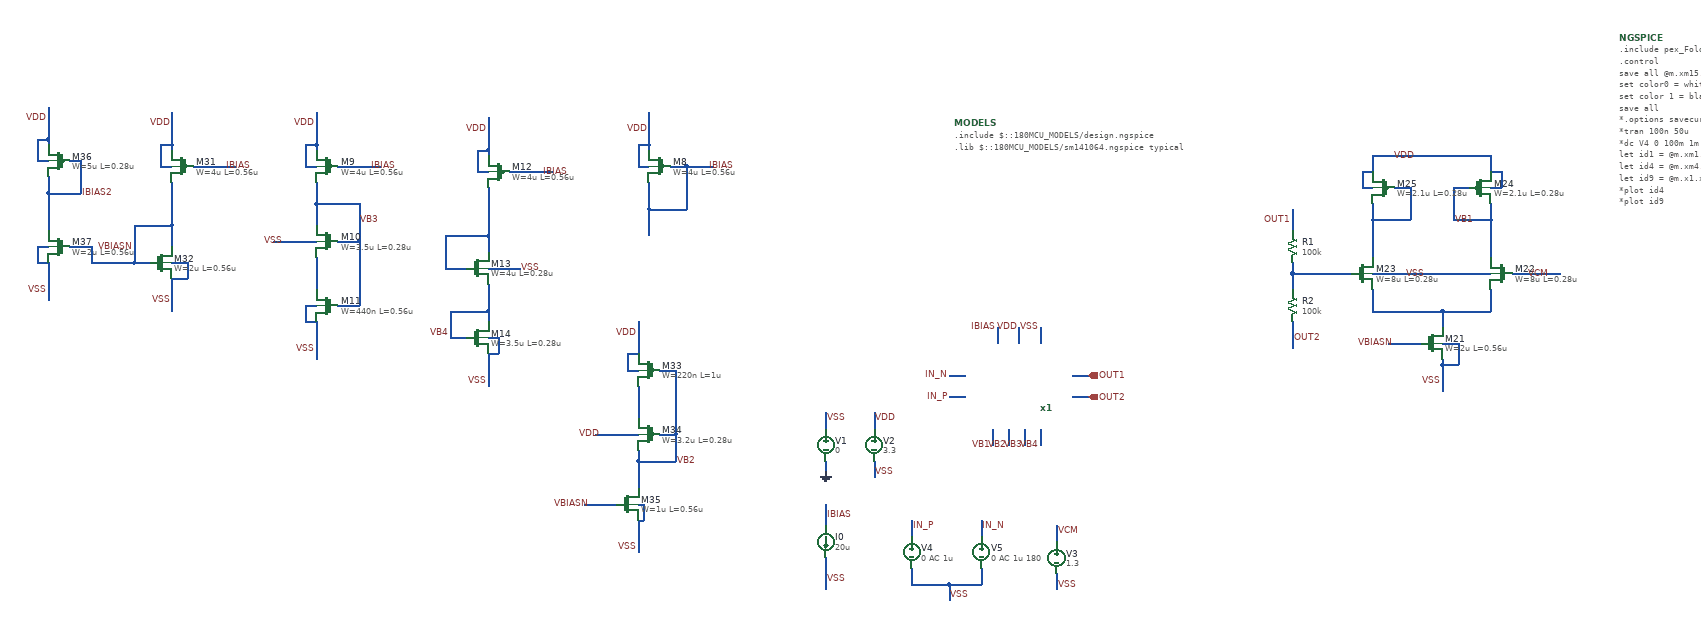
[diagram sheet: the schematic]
v {xschem version=3.1.0 file_version=1.2
}
G {}
K {}
V {}
S {}
E {}
N 10 -20 40 -20 {
lab=IN_N}
N 10 20 40 20 {
lab=IN_P}
N 240 -20 270 -20 {
lab=OUT1}
N 240 20 270 20 {
lab=OUT2}
N 90 80 90 110 {
lab=VB1}
N 120 80 120 110 {
lab=VB2}
N 150 80 150 110 {
lab=VB3}
N 180 80 180 110 {
lab=VB4}
N 100 -110 100 -80 {
lab=IBIAS}
N 140 -110 140 -80 {
lab=VDD}
N 180 -110 180 -80 {
lab=VSS}
N -220 140 -220 160 {
lab=GND}
N -220 50 -220 80 {
lab=VSS}
N -130 50 -130 80 {
lab=VDD}
N -130 140 -130 170 {
lab=VSS}
N 210 260 210 290 {
lab=VCM}
N 210 350 210 380 {
lab=VSS}
N -220 220 -220 260 {
lab=IBIAS}
N -220 320 -220 380 {
lab=VSS}
N -60 250 -60 280 {
lab=IN_P}
N -60 340 -60 370 {
lab=VSS}
N 70 250 70 280 {
lab=IN_N}
N 70 340 70 370 {
lab=VSS}
N 10 370 70 370 {
lab=VSS}
N 10 370 10 400 {
lab=VSS}
N -60 370 10 370 {
lab=VSS}
N -850 -440 -850 -430 {
lab=VDD}
N -870 -400 -850 -400 {
lab=VDD}
N -870 -440 -870 -400 {
lab=VDD}
N -870 -440 -850 -440 {
lab=VDD}
N -810 -400 -730 -400 {
lab=IBIAS}
N -850 -370 -850 -280 {
lab=#net1}
N -850 -280 -850 -250 {
lab=#net1}
N -850 -220 -790 -220 {
lab=VSS}
N -930 -220 -890 -220 {
lab=#net1}
N -930 -280 -930 -220 {
lab=#net1}
N -930 -280 -850 -280 {
lab=#net1}
N -850 -140 -850 -120 {
lab=VB4}
N -920 -90 -890 -90 {
lab=VB4}
N -920 -140 -920 -90 {
lab=VB4}
N -920 -140 -850 -140 {
lab=VB4}
N -850 -60 -850 0 {
lab=VSS}
N -850 -90 -830 -90 {
lab=VSS}
N -830 -90 -830 -60 {
lab=VSS}
N -850 -60 -830 -60 {
lab=VSS}
N -550 -450 -550 -440 {
lab=VDD}
N -570 -410 -550 -410 {
lab=VDD}
N -570 -450 -570 -410 {
lab=VDD}
N -570 -450 -550 -450 {
lab=VDD}
N -480 -410 -430 -410 {
lab=IBIAS}
N -550 -380 -550 -330 {
lab=IBIAS}
N -550 -330 -480 -330 {
lab=IBIAS}
N -480 -410 -480 -330 {
lab=IBIAS}
N -550 -330 -550 -280 {
lab=IBIAS}
N -1170 -450 -1170 -440 {
lab=VDD}
N -1190 -410 -1170 -410 {
lab=VDD}
N -1190 -450 -1190 -410 {
lab=VDD}
N -1190 -450 -1170 -450 {
lab=VDD}
N -1130 -410 -1050 -410 {
lab=IBIAS}
N -1170 -120 -1170 -50 {
lab=VSS}
N -1130 -150 -1090 -150 {
lab=VB3}
N -1170 -240 -1170 -180 {
lab=#net2}
N -1130 -270 -1090 -270 {
lab=VB3}
N -1090 -270 -1090 -150 {
lab=VB3}
N -1090 -340 -1090 -270 {
lab=VB3}
N -1170 -340 -1090 -340 {
lab=VB3}
N -1170 -380 -1170 -340 {
lab=VB3}
N -1170 -340 -1170 -300 {
lab=VB3}
N -1250 -270 -1170 -270 {
lab=VSS}
N -1190 -150 -1170 -150 {
lab=VSS}
N -1190 -150 -1190 -120 {
lab=VSS}
N -1190 -120 -1170 -120 {
lab=VSS}
N -1440 -450 -1440 -440 {
lab=VDD}
N -1460 -410 -1440 -410 {
lab=VDD}
N -1460 -450 -1460 -410 {
lab=VDD}
N -1460 -450 -1440 -450 {
lab=VDD}
N -1400 -410 -1320 -410 {
lab=IBIAS}
N -1440 -300 -1440 -260 {
lab=VBIASN}
N -1440 -200 -1440 -140 {
lab=VSS}
N -1440 -230 -1410 -230 {
lab=VSS}
N -1410 -230 -1410 -200 {
lab=VSS}
N -1440 -200 -1410 -200 {
lab=VSS}
N -1510 -230 -1480 -230 {
lab=VBIASN}
N -1510 -300 -1510 -230 {
lab=VBIASN}
N -1510 -300 -1440 -300 {
lab=VBIASN}
N -570 140 -570 190 {
lab=VB2}
N -570 220 -560 220 {
lab=VSS}
N -560 220 -560 250 {
lab=VSS}
N -570 250 -560 250 {
lab=VSS}
N -570 250 -570 310 {
lab=VSS}
N -670 220 -610 220 {
lab=VBIASN}
N -570 0 -570 60 {
lab=#net3}
N -650 90 -570 90 {
lab=VDD}
N -570 -120 -570 -60 {
lab=VDD}
N -530 -30 -500 -30 {
lab=VB2}
N -500 90 -500 140 {
lab=VB2}
N -570 140 -500 140 {
lab=VB2}
N -530 90 -500 90 {
lab=VB2}
N -590 -30 -570 -30 {
lab=VDD}
N -590 -60 -590 -30 {
lab=VDD}
N -590 -60 -570 -60 {
lab=VDD}
N -1670 -460 -1670 -450 {
lab=VDD}
N -1690 -420 -1670 -420 {
lab=VDD}
N -1690 -460 -1690 -420 {
lab=VDD}
N -1690 -460 -1670 -460 {
lab=VDD}
N -1670 -230 -1670 -160 {
lab=VSS}
N -1690 -260 -1670 -260 {
lab=VSS}
N -1690 -260 -1690 -230 {
lab=VSS}
N -1690 -230 -1670 -230 {
lab=VSS}
N -1630 -260 -1590 -260 {
lab=VBIASN}
N -1590 -260 -1590 -230 {
lab=VBIASN}
N -1590 -230 -1510 -230 {
lab=VBIASN}
N -1670 -360 -1670 -290 {
lab=IBIAS2}
N -1630 -420 -1610 -420 {
lab=IBIAS2}
N -1610 -420 -1610 -360 {
lab=IBIAS2}
N -1670 -360 -1610 -360 {
lab=IBIAS2}
N -850 -500 -850 -440 {
lab=VDD}
N -850 -190 -850 -140 {
lab=VB4}
N -550 -510 -550 -450 {
lab=VDD}
N -510 -410 -480 -410 {
lab=IBIAS}
N -1170 -510 -1170 -450 {
lab=VDD}
N -1440 -510 -1440 -450 {
lab=VDD}
N -1440 -380 -1440 -300 {
lab=VBIASN}
N -570 120 -570 140 {
lab=VB2}
N -500 -30 -500 90 {
lab=VB2}
N -1670 -520 -1670 -460 {
lab=VDD}
N -1670 -390 -1670 -360 {
lab=IBIAS2}
N 800 -430 800 -400 {
lab=VDD}
N 800 -430 1020 -430 {
lab=VDD}
N 1020 -430 1020 -400 {
lab=VDD}
N 1020 -310 1020 -240 {
lab=VB1}
N 800 -310 800 -240 {
lab=#net4}
N 840 -370 870 -370 {
lab=#net4}
N 870 -370 870 -310 {
lab=#net4}
N 800 -310 870 -310 {
lab=#net4}
N 950 -370 980 -370 {
lab=VB1}
N 950 -370 950 -310 {
lab=VB1}
N 950 -310 1020 -310 {
lab=VB1}
N 1020 -180 1020 -140 {
lab=#net5}
N 930 -140 1020 -140 {
lab=#net5}
N 800 -180 800 -140 {
lab=#net5}
N 930 -140 930 -110 {
lab=#net5}
N 930 -40 930 10 {
lab=VSS}
N 830 -80 890 -80 {
lab=VBIASN}
N 650 -330 650 -290 {
lab=OUT1}
N 650 -210 650 -180 {
lab=#net6}
N 650 -120 650 -70 {
lab=OUT2}
N 650 -210 760 -210 {
lab=#net6}
N 1060 -210 1150 -210 {
lab=VCM}
N 780 -370 800 -370 {
lab=VDD}
N 780 -400 780 -370 {
lab=VDD}
N 780 -400 800 -400 {
lab=VDD}
N 1020 -370 1040 -370 {
lab=VDD}
N 1040 -400 1040 -370 {
lab=VDD}
N 1020 -400 1040 -400 {
lab=VDD}
N 800 -210 1020 -210 {
lab=VSS}
N 930 -80 960 -80 {
lab=VSS}
N 960 -80 960 -40 {
lab=VSS}
N 930 -40 960 -40 {
lab=VSS}
N 800 -340 800 -310 {
lab=#net4}
N 1020 -340 1020 -310 {
lab=VB1}
N 800 -140 930 -140 {
lab=#net5}
N 650 -230 650 -210 {
lab=#net6}
N 930 -50 930 -40 {
lab=VSS}
C {devices/lab_pin.sym} 10 -20 0 0 {name=p1 sig_type=std_logic lab=IN_N}
C {devices/lab_pin.sym} 10 20 0 0 {name=p2 sig_type=std_logic lab=IN_P}
C {devices/lab_pin.sym} 100 -110 1 0 {name=p3 sig_type=std_logic lab=IBIAS}
C {devices/lab_pin.sym} 140 -110 1 0 {name=p4 sig_type=std_logic lab=VDD}
C {devices/lab_pin.sym} 180 -110 1 0 {name=p5 sig_type=std_logic lab=VSS}
C {devices/lab_pin.sym} 90 110 3 0 {name=p6 sig_type=std_logic lab=VB1}
C {devices/lab_pin.sym} 120 110 3 0 {name=p7 sig_type=std_logic lab=VB2}
C {devices/lab_pin.sym} 150 110 3 0 {name=p8 sig_type=std_logic lab=VB3}
C {devices/lab_pin.sym} 180 110 3 0 {name=p9 sig_type=std_logic lab=VB4}
C {devices/opin.sym} 270 -20 0 0 {name=p10 lab=OUT1}
C {devices/opin.sym} 270 20 0 0 {name=p11 lab=OUT2}
C {devices/code_shown.sym} 20 -490 0 0 {name=MODELS only_toplevel=true
format="tcleval( @value )"
value="
.include $::180MCU_MODELS/design.ngspice
.lib $::180MCU_MODELS/sm141064.ngspice typical
"}
C {devices/vsource.sym} -220 110 0 0 {name=V1 value=0}
C {devices/gnd.sym} -220 160 0 0 {name=l1 lab=GND}
C {devices/lab_pin.sym} -220 60 0 1 {name=p33 sig_type=std_logic lab=VSS}
C {devices/vsource.sym} -130 110 0 0 {name=V2 value=3.3}
C {devices/lab_pin.sym} -130 60 0 1 {name=p34 sig_type=std_logic lab=VDD}
C {devices/lab_pin.sym} -130 160 0 1 {name=p35 sig_type=std_logic lab=VSS}
C {devices/code_shown.sym} 1260 -650 0 0 {name=NGSPICE only_toplevel=true
value="
.include "pex_Folded_Diff_Op_Amp_Layout.spice"
.control
save all @m.xm15.m0[id] @m.xm1.m0[id] @m.xm4.m0[id] @m.x1.xm9.m0[id]
set color0 = white
set color 1 = black
save all
*.options savecurrents

*tran 100n 50u
*dc V4 0 100m 1m
let id1 = @m.xm1.m0[id] 
let id4 = @m.xm4.m0[id]
let id9 = @m.x1.xm9.m0[id]
*plot id4 
*plot id9
plot v(OUT1) v(OUT2)
*plot v(IN1) v(IN2)
*plot v(IN1P) v(IN1N)
*print mean(@m.xm2.m0[vds]) mean(@m.xm4.m0[vds]) mean(@m.xm7.m0[vds])

ac dec 50 1 1e9
let tf = OUT1/IN_P
let gain = db(tf)
let phase = (180/pi)*ph(tf)
plot gain
plot phase 

*write pmos_nmos.raw
*let vdiff = @m.xm1.m0[vdsat]+vds
*plot @m.xm1.m0[vdsat]
*tran 1u 2m
*let gain = (maximum(out1)-minimum(out2) )* 1000
*print vbb



*plot vdiff
display all
.endc
"}
C {devices/vsource.sym} 210 320 0 0 {name=V3 value=1.3}
C {devices/lab_pin.sym} 210 270 0 1 {name=p20 sig_type=std_logic lab=VCM}
C {devices/lab_pin.sym} 210 370 0 1 {name=p21 sig_type=std_logic lab=VSS}
C {devices/isource.sym} -220 290 0 0 {name=I0 value=20u}
C {devices/lab_pin.sym} -220 360 0 1 {name=p49 sig_type=std_logic lab=VSS}
C {devices/lab_wire.sym} -220 240 0 1 {name=p50 sig_type=std_logic lab=IBIAS}
C {devices/vsource.sym} -60 310 0 0 {name=V4 value="0 AC 1u"}
C {devices/lab_pin.sym} -60 260 0 1 {name=p64 sig_type=std_logic lab=IN_P}
C {devices/lab_pin.sym} 70 260 0 1 {name=p65 sig_type=std_logic lab=IN_N}
C {devices/lab_pin.sym} 10 390 0 1 {name=p66 sig_type=std_logic lab=VSS}
C {devices/vsource.sym} 70 310 0 0 {name=V5 value="0 AC 1u 180"}
C {symbols/pfet_03v3.sym} -830 -400 0 1 {name=M12
L=0.56u
W=4u
nf=1
m=1
ad="'int((nf+1)/2) * W/nf * 0.18u'"
pd="'2*int((nf+1)/2) * (W/nf + 0.18u)'"
as="'int((nf+2)/2) * W/nf * 0.18u'"
ps="'2*int((nf+2)/2) * (W/nf + 0.18u)'"
nrd="'0.18u / W'" nrs="'0.18u / W'"
sa=0 sb=0 sd=0
model=pfet_03v3
spiceprefix=X
}
C {symbols/nfet_03v3.sym} -870 -220 0 0 {name=M13
L=0.28u
W=4u
nf=1
m=1
ad="'int((nf+1)/2) * W/nf * 0.18u'"
pd="'2*int((nf+1)/2) * (W/nf + 0.18u)'"
as="'int((nf+2)/2) * W/nf * 0.18u'"
ps="'2*int((nf+2)/2) * (W/nf + 0.18u)'"
nrd="'0.18u / W'" nrs="'0.18u / W'"
sa=0 sb=0 sd=0
model=nfet_03v3
spiceprefix=X
}
C {symbols/nfet_03v3.sym} -870 -90 0 0 {name=M14
L=0.28u
W=3.5u
nf=1
m=1
ad="'int((nf+1)/2) * W/nf * 0.18u'"
pd="'2*int((nf+1)/2) * (W/nf + 0.18u)'"
as="'int((nf+2)/2) * W/nf * 0.18u'"
ps="'2*int((nf+2)/2) * (W/nf + 0.18u)'"
nrd="'0.18u / W'" nrs="'0.18u / W'"
sa=0 sb=0 sd=0
model=nfet_03v3
spiceprefix=X
}
C {devices/lab_wire.sym} -850 -10 0 0 {name=p13 sig_type=std_logic lab=VSS}
C {symbols/pfet_03v3.sym} -530 -410 0 1 {name=M8
L=0.56u
W=4u
nf=1
m=1
ad="'int((nf+1)/2) * W/nf * 0.18u'"
pd="'2*int((nf+1)/2) * (W/nf + 0.18u)'"
as="'int((nf+2)/2) * W/nf * 0.18u'"
ps="'2*int((nf+2)/2) * (W/nf + 0.18u)'"
nrd="'0.18u / W'" nrs="'0.18u / W'"
sa=0 sb=0 sd=0
model=pfet_03v3
spiceprefix=X
}
C {devices/lab_wire.sym} -550 -480 0 0 {name=p15 sig_type=std_logic lab=VDD}
C {devices/lab_wire.sym} -850 -480 0 0 {name=p16 sig_type=std_logic lab=VDD}
C {devices/lab_wire.sym} -790 -220 0 1 {name=p17 sig_type=std_logic lab=VSS}
C {devices/lab_wire.sym} -440 -410 0 1 {name=p23 sig_type=std_logic lab=IBIAS}
C {devices/lab_wire.sym} -750 -400 0 1 {name=p61 sig_type=std_logic lab=IBIAS}
C {devices/lab_wire.sym} -920 -100 0 0 {name=p62 sig_type=std_logic lab=VB4}
C {symbols/pfet_03v3.sym} -1150 -410 0 1 {name=M9
L=0.56u
W=4u
nf=1
m=1
ad="'int((nf+1)/2) * W/nf * 0.18u'"
pd="'2*int((nf+1)/2) * (W/nf + 0.18u)'"
as="'int((nf+2)/2) * W/nf * 0.18u'"
ps="'2*int((nf+2)/2) * (W/nf + 0.18u)'"
nrd="'0.18u / W'" nrs="'0.18u / W'"
sa=0 sb=0 sd=0
model=pfet_03v3
spiceprefix=X
}
C {devices/lab_wire.sym} -1170 -490 0 0 {name=p63 sig_type=std_logic lab=VDD}
C {devices/lab_wire.sym} -1070 -410 0 1 {name=p68 sig_type=std_logic lab=IBIAS}
C {symbols/nfet_03v3.sym} -1150 -270 0 1 {name=M10
L=0.28u
W=3.5u
nf=1
m=1
ad="'int((nf+1)/2) * W/nf * 0.18u'"
pd="'2*int((nf+1)/2) * (W/nf + 0.18u)'"
as="'int((nf+2)/2) * W/nf * 0.18u'"
ps="'2*int((nf+2)/2) * (W/nf + 0.18u)'"
nrd="'0.18u / W'" nrs="'0.18u / W'"
sa=0 sb=0 sd=0
model=nfet_03v3
spiceprefix=X
}
C {symbols/nfet_03v3.sym} -1150 -150 0 1 {name=M11
L=0.56u
W=440n
nf=1
m=1
ad="'int((nf+1)/2) * W/nf * 0.18u'"
pd="'2*int((nf+1)/2) * (W/nf + 0.18u)'"
as="'int((nf+2)/2) * W/nf * 0.18u'"
ps="'2*int((nf+2)/2) * (W/nf + 0.18u)'"
nrd="'0.18u / W'" nrs="'0.18u / W'"
sa=0 sb=0 sd=0
model=nfet_03v3
spiceprefix=X
}
C {devices/lab_wire.sym} -1230 -270 0 0 {name=p69 sig_type=std_logic lab=VSS}
C {devices/lab_wire.sym} -1090 -310 0 1 {name=p70 sig_type=std_logic lab=VB3}
C {symbols/pfet_03v3.sym} -1420 -410 0 1 {name=M31
L=0.56u
W=4u
nf=1
m=1
ad="'int((nf+1)/2) * W/nf * 0.18u'"
pd="'2*int((nf+1)/2) * (W/nf + 0.18u)'"
as="'int((nf+2)/2) * W/nf * 0.18u'"
ps="'2*int((nf+2)/2) * (W/nf + 0.18u)'"
nrd="'0.18u / W'" nrs="'0.18u / W'"
sa=0 sb=0 sd=0
model=pfet_03v3
spiceprefix=X
}
C {devices/lab_wire.sym} -1440 -490 0 0 {name=p71 sig_type=std_logic lab=VDD}
C {devices/lab_wire.sym} -1340 -410 0 1 {name=p72 sig_type=std_logic lab=IBIAS}
C {symbols/nfet_03v3.sym} -1460 -230 0 0 {name=M32
L=0.56u
W=2u
nf=1
m=1
ad="'int((nf+1)/2) * W/nf * 0.18u'"
pd="'2*int((nf+1)/2) * (W/nf + 0.18u)'"
as="'int((nf+2)/2) * W/nf * 0.18u'"
ps="'2*int((nf+2)/2) * (W/nf + 0.18u)'"
nrd="'0.18u / W'" nrs="'0.18u / W'"
sa=0 sb=0 sd=0
model=nfet_03v3
spiceprefix=X
}
C {devices/lab_wire.sym} -1510 -260 0 0 {name=p73 sig_type=std_logic lab=VBIASN}
C {symbols/pfet_03v3.sym} -550 -30 0 1 {name=M33
L=1u
W=220n
nf=1
m=1
ad="'int((nf+1)/2) * W/nf * 0.18u'"
pd="'2*int((nf+1)/2) * (W/nf + 0.18u)'"
as="'int((nf+2)/2) * W/nf * 0.18u'"
ps="'2*int((nf+2)/2) * (W/nf + 0.18u)'"
nrd="'0.18u / W'" nrs="'0.18u / W'"
sa=0 sb=0 sd=0
model=pfet_03v3
spiceprefix=X
}
C {symbols/pfet_03v3.sym} -550 90 0 1 {name=M34
L=0.28u
W=3.2u
nf=1
m=1
ad="'int((nf+1)/2) * W/nf * 0.18u'"
pd="'2*int((nf+1)/2) * (W/nf + 0.18u)'"
as="'int((nf+2)/2) * W/nf * 0.18u'"
ps="'2*int((nf+2)/2) * (W/nf + 0.18u)'"
nrd="'0.18u / W'" nrs="'0.18u / W'"
sa=0 sb=0 sd=0
model=pfet_03v3
spiceprefix=X
}
C {symbols/nfet_03v3.sym} -590 220 0 0 {name=M35
L=0.56u
W=1u
nf=1
m=1
ad="'int((nf+1)/2) * W/nf * 0.18u'"
pd="'2*int((nf+1)/2) * (W/nf + 0.18u)'"
as="'int((nf+2)/2) * W/nf * 0.18u'"
ps="'2*int((nf+2)/2) * (W/nf + 0.18u)'"
nrd="'0.18u / W'" nrs="'0.18u / W'"
sa=0 sb=0 sd=0
model=nfet_03v3
spiceprefix=X
}
C {devices/lab_wire.sym} -570 -100 0 0 {name=p74 sig_type=std_logic lab=VDD}
C {devices/lab_wire.sym} -640 90 0 0 {name=p75 sig_type=std_logic lab=VDD}
C {devices/lab_wire.sym} -570 300 0 0 {name=p76 sig_type=std_logic lab=VSS}
C {devices/lab_wire.sym} -660 220 0 0 {name=p77 sig_type=std_logic lab=VBIASN}
C {devices/lab_wire.sym} -500 140 0 1 {name=p78 sig_type=std_logic lab=VB2}
C {devices/lab_wire.sym} -1170 -70 0 0 {name=p79 sig_type=std_logic lab=VSS}
C {devices/lab_wire.sym} -1440 -160 0 0 {name=p80 sig_type=std_logic lab=VSS}
C {symbols/pfet_03v3.sym} -1650 -420 0 1 {name=M36
L=0.28u
W=5u
nf=1
m=1
ad="'int((nf+1)/2) * W/nf * 0.18u'"
pd="'2*int((nf+1)/2) * (W/nf + 0.18u)'"
as="'int((nf+2)/2) * W/nf * 0.18u'"
ps="'2*int((nf+2)/2) * (W/nf + 0.18u)'"
nrd="'0.18u / W'" nrs="'0.18u / W'"
sa=0 sb=0 sd=0
model=pfet_03v3
spiceprefix=X
}
C {devices/lab_wire.sym} -1670 -500 0 0 {name=p81 sig_type=std_logic lab=VDD}
C {symbols/nfet_03v3.sym} -1650 -260 0 1 {name=M37
L=0.56u
W=2u
nf=1
m=1
ad="'int((nf+1)/2) * W/nf * 0.18u'"
pd="'2*int((nf+1)/2) * (W/nf + 0.18u)'"
as="'int((nf+2)/2) * W/nf * 0.18u'"
ps="'2*int((nf+2)/2) * (W/nf + 0.18u)'"
nrd="'0.18u / W'" nrs="'0.18u / W'"
sa=0 sb=0 sd=0
model=nfet_03v3
spiceprefix=X
}
C {devices/lab_wire.sym} -1610 -360 0 1 {name=p82 sig_type=std_logic lab=IBIAS2}
C {devices/lab_wire.sym} -1670 -180 0 0 {name=p83 sig_type=std_logic lab=VSS}
C {symbols/nfet_03v3.sym} 910 -80 0 0 {name=M21
L=0.56u
W=2u
nf=1
m=1
ad="'int((nf+1)/2) * W/nf * 0.18u'"
pd="'2*int((nf+1)/2) * (W/nf + 0.18u)'"
as="'int((nf+2)/2) * W/nf * 0.18u'"
ps="'2*int((nf+2)/2) * (W/nf + 0.18u)'"
nrd="'0.18u / W'" nrs="'0.18u / W'"
sa=0 sb=0 sd=0
model=nfet_03v3
spiceprefix=X
}
C {symbols/nfet_03v3.sym} 1040 -210 0 1 {name=M22
L=0.28u
W=8u
nf=1
m=1
ad="'int((nf+1)/2) * W/nf * 0.18u'"
pd="'2*int((nf+1)/2) * (W/nf + 0.18u)'"
as="'int((nf+2)/2) * W/nf * 0.18u'"
ps="'2*int((nf+2)/2) * (W/nf + 0.18u)'"
nrd="'0.18u / W'" nrs="'0.18u / W'"
sa=0 sb=0 sd=0
model=nfet_03v3
spiceprefix=X
}
C {symbols/nfet_03v3.sym} 780 -210 0 0 {name=M23
L=0.28u
W=8u
nf=1
m=1
ad="'int((nf+1)/2) * W/nf * 0.18u'"
pd="'2*int((nf+1)/2) * (W/nf + 0.18u)'"
as="'int((nf+2)/2) * W/nf * 0.18u'"
ps="'2*int((nf+2)/2) * (W/nf + 0.18u)'"
nrd="'0.18u / W'" nrs="'0.18u / W'"
sa=0 sb=0 sd=0
model=nfet_03v3
spiceprefix=X
}
C {symbols/pfet_03v3.sym} 1000 -370 0 0 {name=M24
L=0.28u
W=2.1u
nf=1
m=1
ad="'int((nf+1)/2) * W/nf * 0.18u'"
pd="'2*int((nf+1)/2) * (W/nf + 0.18u)'"
as="'int((nf+2)/2) * W/nf * 0.18u'"
ps="'2*int((nf+2)/2) * (W/nf + 0.18u)'"
nrd="'0.18u / W'" nrs="'0.18u / W'"
sa=0 sb=0 sd=0
model=pfet_03v3
spiceprefix=X
}
C {symbols/pfet_03v3.sym} 820 -370 0 1 {name=M25
L=0.28u
W=2.1u
nf=1
m=1
ad="'int((nf+1)/2) * W/nf * 0.18u'"
pd="'2*int((nf+1)/2) * (W/nf + 0.18u)'"
as="'int((nf+2)/2) * W/nf * 0.18u'"
ps="'2*int((nf+2)/2) * (W/nf + 0.18u)'"
nrd="'0.18u / W'" nrs="'0.18u / W'"
sa=0 sb=0 sd=0
model=pfet_03v3
spiceprefix=X
}
C {devices/lab_wire.sym} 840 -80 0 0 {name=p31 sig_type=std_logic lab=VBIASN}
C {devices/res.sym} 650 -260 0 0 {name=R1
value=100k
footprint=1206
device=resistor
m=1}
C {devices/res.sym} 650 -150 0 0 {name=R2
value=100k
footprint=1206
device=resistor
m=1}
C {devices/lab_wire.sym} 880 -430 0 0 {name=p32 sig_type=std_logic lab=VDD}
C {devices/lab_wire.sym} 930 -10 0 0 {name=p12 sig_type=std_logic lab=VSS}
C {devices/lab_wire.sym} 650 -310 0 0 {name=p36 sig_type=std_logic lab=OUT1}
C {devices/lab_wire.sym} 650 -90 0 1 {name=p37 sig_type=std_logic lab=OUT2}
C {devices/lab_wire.sym} 1130 -210 0 0 {name=p51 sig_type=std_logic lab=VCM}
C {devices/lab_wire.sym} 900 -210 0 0 {name=p47 sig_type=std_logic lab=VSS}
C {devices/lab_wire.sym} 990 -310 0 0 {name=p14 sig_type=std_logic lab=VB1}
C {Folded_Cascode_Diff_PEX.sym} 180 40 0 0 {name=x1}
